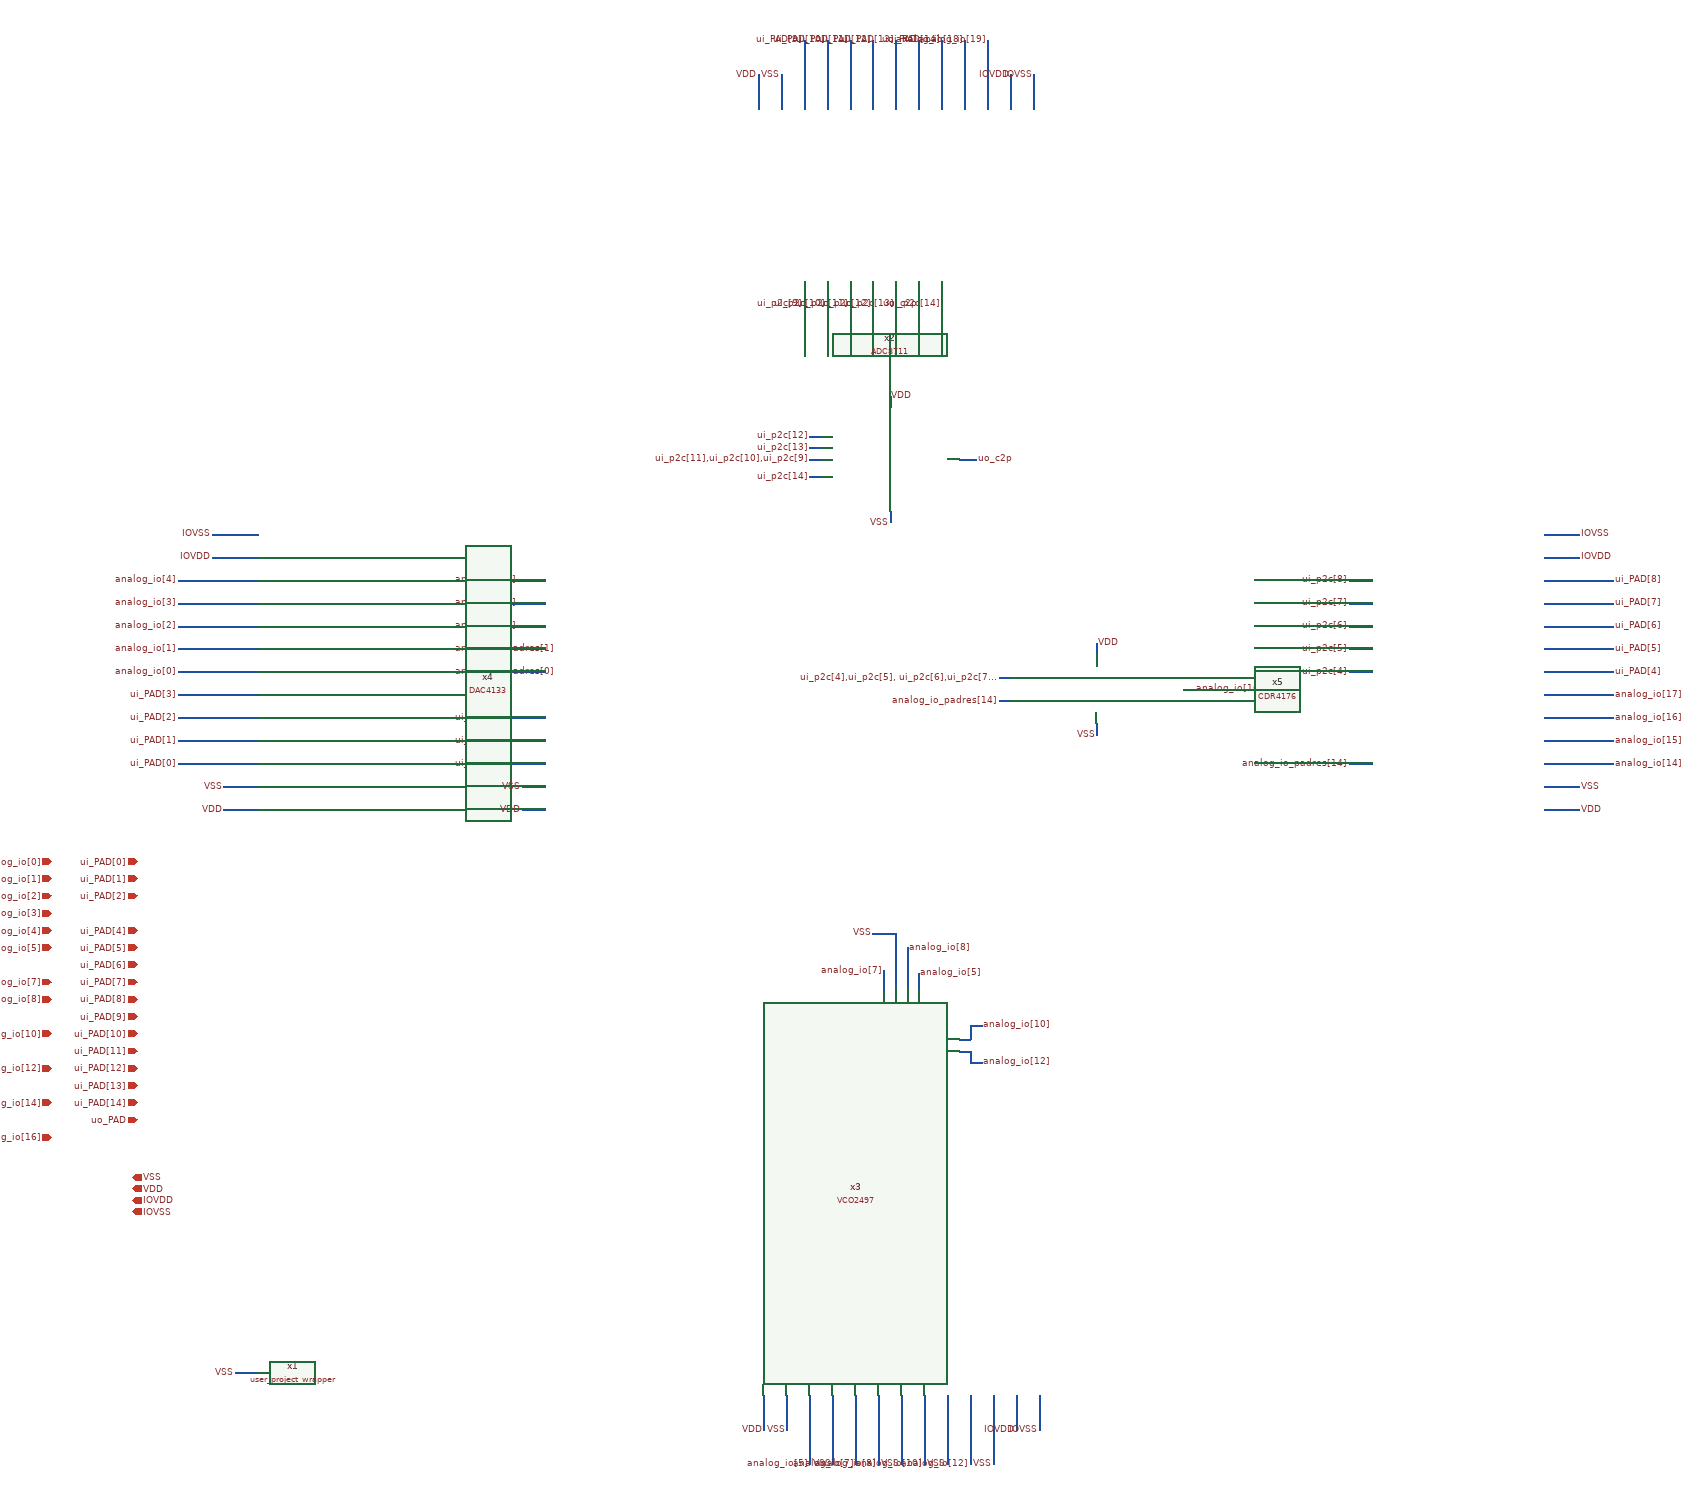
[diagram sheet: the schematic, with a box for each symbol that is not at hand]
v {xschem version=3.4.8RC file_version=1.3}
G {}
K {}
V {}
S {}
F {}
E {}
N 300 -1180 500 -1180 {lab=ui_p2c[2]}
N 2240 -1500 2300 -1500 {lab=IOVSS}
N 2240 -1460 2300 -1460 {lab=IOVDD}
N 2240 -1420 2360 -1420 {lab=ui_PAD[8]}
N 2240 -1100 2360 -1100 {lab=analog_io[14]}
N 2240 -1380 2360 -1380 {lab=ui_PAD[7]}
N 2240 -1260 2360 -1260 {lab=ui_PAD[4]}
N 2240 -1140 2360 -1140 {lab=analog_io[15]}
N 960 0 960 120 {lab=analog_io[5]}
N 1000 0 1000 120 {lab=VSS}
N 1040 0 1040 120 {lab=analog_io[7]}
N 1080 0 1080 120 {lab=analog_io[8]}
N 1120 0 1120 120 {lab=VSS}
N 1160 0 1160 120 {lab=analog_io[10]}
N 1200 0 1200 120 {lab=VSS}
N 1240 0 1240 120 {lab=analog_io[12]}
N 1280 0 1280 120 {lab=VSS}
N -40 -40 0 -40 {lab=VSS}
N 2240 -1340 2360 -1340 {lab=ui_PAD[6]}
N 2240 -1300 2360 -1300 {lab=ui_PAD[5]}
N 2240 -1180 2360 -1180 {lab=analog_io[16]}
N 2240 -1220 2360 -1220 {lab=analog_io[17]}
N 300 -1140 500 -1140 {lab=ui_p2c[1]}
N 300 -1100 500 -1100 {lab=ui_p2c[0]}
N -140 -1420 0 -1420 {lab=analog_io[4]}
N -140 -1380 0 -1380 {lab=analog_io[3]}
N -140 -1340 0 -1340 {lab=analog_io[2]}
N -140 -1300 0 -1300 {lab=analog_io[1]}
N -140 -1260 0 -1260 {lab=analog_io[0]}
N -140 -1220 0 -1220 {lab=ui_PAD[3]}
N -140 -1180 0 -1180 {lab=ui_PAD[2]}
N -140 -1140 0 -1140 {lab=ui_PAD[1]}
N -140 -1100 0 -1100 {lab=ui_PAD[0]}
N -80 -1500 -0 -1500 {lab=IOVSS}
N -80 -1460 -0 -1460 {lab=IOVDD}
N -60 -1060 -0 -1060 {lab=VSS}
N -60 -1020 -0 -1020 {lab=VDD}
N 880 0 880 60 {lab=VDD}
N 920 0 920 60 {lab=VSS}
N 1320 0 1320 60 {lab=IOVDD}
N 1360 0 1360 60 {lab=IOVSS}
N 2240 -1020 2300 -1020 {lab=VDD}
N 2240 -1060 2300 -1060 {lab=VSS}
N 1900 -1100 1940 -1100 {lab=analog_io_padres[14]}
N 1900 -1420 1940 -1420 {lab=ui_p2c[8]}
N 1900 -1380 1940 -1380 {lab=ui_p2c[7]}
N 1900 -1340 1940 -1340 {lab=ui_p2c[6]}
N 1900 -1300 1940 -1300 {lab=ui_p2c[5]}
N 1900 -1260 1940 -1260 {lab=ui_p2c[4]}
N 870 -2300 870 -2240 {lab=VDD}
N 910 -2300 910 -2240 {lab=VSS}
N 950 -2360 950 -2240 {lab=ui_PAD[9]}
N 990 -2360 990 -2240 {lab=ui_PAD[10]}
N 1030 -2360 1030 -2240 {lab=ui_PAD[11]}
N 1070 -2360 1070 -2240 {lab=ui_PAD[12]}
N 1110 -2360 1110 -2240 {lab=ui_PAD[13]}
N 1150 -2360 1150 -2240 {lab=uo_PAD}
N 1190 -2360 1190 -2240 {lab=ui_PAD[14]}
N 1230 -2360 1230 -2240 {lab=analog_io[18]}
N 1270 -2360 1270 -2240 {lab=analog_io[19]}
N 1310 -2300 1310 -2240 {lab=IOVDD}
N 1350 -2300 1350 -2240 {lab=IOVSS}
N 950 -1940 950 -1900 {lab=ui_p2c[9]}
N 990 -1940 990 -1900 {lab=ui_p2c[10]}
N 1030 -1940 1030 -1900 {lab=ui_p2c[11]}
N 1070 -1940 1070 -1900 {lab=ui_p2c[12]}
N 1110 -1940 1110 -1900 {lab=ui_p2c[13]}
N 1150 -1940 1150 -1900 {lab=uo_c2p}
N 1190 -1940 1190 -1900 {lab=ui_p2c[14]}
N 1610 -1230 1630 -1230 {lab=analog_io[16]}
N 1290 -1210 1310 -1210 {lab=analog_io_padres[14]}
N 1290 -1250 1310 -1250 {lab="ui_p2c[4],ui_p2c[5],
ui_p2c[6],ui_p2c[7],
ui_p2c[8]"}
N 1460 -1310 1460 -1290 {lab=VDD}
N 1460 -1170 1460 -1150 {lab=VSS}
N 1100 -1740 1100 -1720 {lab=VDD}
N 1100 -1540 1100 -1520 {lab=VSS}
N 960 -1600 980 -1600 {lab=ui_p2c[14]}
N 1220 -1630 1250 -1630 {lab=uo_c2p}
N 960 -1650 980 -1650 {lab=ui_p2c[13]}
N 960 -1670 980 -1670 {lab=ui_p2c[12]}
N 960 -1630 980 -1630 {lab=ui_p2c[11],ui_p2c[10],ui_p2c[9]}
N 1130 -780 1130 -710 {lab=analog_io[8]}
N 1220 -620 1240 -620 {lab=analog_io[10]}
N 1240 -645 1240 -620 {lab=analog_io[10]}
N 1240 -645 1260 -645 {lab=analog_io[10]}
N 1220 -600 1240 -600 {lab=analog_io[12]}
N 1240 -600 1240 -580 {lab=analog_io[12]}
N 1240 -580 1260 -580 {lab=analog_io[12]}
N 460 -1060 500 -1060 {lab=VSS}
N 460 -1020 500 -1020 {lab=VDD}
N 340 -1420 500 -1420 {lab=analog_io[4]}
N 340 -1380 500 -1380 {lab=analog_io[3]}
N 340 -1340 500 -1340 {lab=analog_io[2]}
N 300 -1300 500 -1300 {lab=analog_io_padres[1]}
N 300 -1260 500 -1260 {lab=analog_io_padres[0]}
N 1108.75 -805 1108.75 -710 {lab=VSS}
N 1070 -805 1108.75 -805 {lab=VSS}
N 1088.75 -740 1088.75 -703.75 {lab=analog_io[7]}
N 1088.75 -740 1090 -740 {lab=analog_io[7]}
N 1148.75 -735 1148.75 -705.9375 {lab=analog_io[5]}
N 1148.75 -735 1150 -735 {lab=analog_io[5]}
C {lab_wire.sym} 1030 -2360 3 1 {name=p12 sig_type=std_logic lab=ui_PAD[11]	}
C {lab_wire.sym} 990 -2360 3 1 {name=p13 sig_type=std_logic lab=ui_PAD[10]	}
C {lab_wire.sym} 1190 -2360 3 1 {name=p15 sig_type=std_logic lab=ui_PAD[14]	}
C {lab_wire.sym} 1070 -2360 3 1 {name=p16 sig_type=std_logic lab=ui_PAD[12]	}
C {lab_wire.sym} 950 -2360 3 1 {name=p17 sig_type=std_logic lab=ui_PAD[9]	}
C {lab_wire.sym} 1110 -2360 3 1 {name=p18 sig_type=std_logic lab=ui_PAD[13]	}
C {lab_wire.sym} 1150 -2360 3 1 {name=p19 sig_type=std_logic lab=uo_PAD	}
C {lab_wire.sym} 910 -2300 3 1 {name=p23 sig_type=std_logic lab=VSS}
C {lab_wire.sym} 870 -2300 3 1 {name=p24 sig_type=std_logic lab=VDD	}
C {lab_wire.sym} 340 -1340 0 1 {name=p45 sig_type=std_logic lab=analog_io[2]	}
C {lab_wire.sym} 340 -1300 0 1 {name=p46 sig_type=std_logic lab=analog_io_padres[1]	}
C {lab_wire.sym} -140 -1420 0 0 {name=p59 sig_type=std_logic lab=analog_io[4]	}
C {lab_wire.sym} 2300 -1060 0 1 {name=p63 sig_type=std_logic lab=VSS}
C {lab_wire.sym} 2300 -1020 0 1 {name=p64 sig_type=std_logic lab=VDD}
C {lab_wire.sym} 2360 -1180 0 1 {name=p67 sig_type=std_logic lab=analog_io[16]}
C {lab_wire.sym} 2360 -1340 0 1 {name=p68 sig_type=std_logic lab=ui_PAD[6]}
C {lab_wire.sym} 1900 -1100 0 0 {name=p72 sig_type=std_logic lab=analog_io_padres[14]}
C {lab_wire.sym} 2360 -1380 0 1 {name=p77 sig_type=std_logic lab=ui_PAD[7]	}
C {lab_wire.sym} 2360 -1260 0 1 {name=p78 sig_type=std_logic lab=ui_PAD[4]	}
C {lab_wire.sym} 2360 -1100 0 1 {name=p79 sig_type=std_logic lab=analog_io[14]	}
C {lab_wire.sym} 920 60 3 0 {name=p82 sig_type=std_logic lab=VSS}
C {lab_wire.sym} 1000 120 3 0 {name=p84 sig_type=std_logic lab=VSS	}
C {lab_wire.sym} 1040 120 3 0 {name=p85 sig_type=std_logic lab=analog_io[7]	}
C {lab_wire.sym} 1080 120 3 0 {name=p86 sig_type=std_logic lab=analog_io[8]	}
C {lab_wire.sym} 1120 120 3 0 {name=p87 sig_type=std_logic lab=VSS	}
C {lab_wire.sym} 1160 120 3 0 {name=p88 sig_type=std_logic lab=analog_io[10]	}
C {lab_wire.sym} 1200 120 3 0 {name=p89 sig_type=std_logic lab=VSS	}
C {lab_wire.sym} 1240 120 3 0 {name=p90 sig_type=std_logic lab=analog_io[12]	}
C {lab_wire.sym} 1280 120 3 0 {name=p91 sig_type=std_logic lab=VSS	}
C {lab_wire.sym} 960 120 3 0 {name=p102 sig_type=std_logic lab=analog_io[5]	}
C {iopin.sym} -360 -630 2 0 {name=p103 lab=analog_io[10]}
C {iopin.sym} -360 -810 2 0 {name=p104 lab=analog_io[4]}
C {iopin.sym} -360 -930 2 0 {name=p105 lab=analog_io[0]}
C {iopin.sym} -360 -900 2 0 {name=p106 lab=analog_io[1]}
C {iopin.sym} -360 -780 2 0 {name=p116 lab=analog_io[5]}
C {iopin.sym} -360 -720 2 0 {name=p118 lab=analog_io[7]}
C {iopin.sym} -360 -570 2 0 {name=p120 lab=analog_io[12]}
C {iopin.sym} -360 -510 2 0 {name=p122 lab=analog_io[14]}
C {iopin.sym} -360 -450 2 0 {name=p124 lab=analog_io[16]}
C {iopin.sym} -360 -690 2 0 {name=p128 lab=analog_io[8]}
C {iopin.sym} -210 -930 2 0 {name=p129 lab=ui_PAD[0]}
C {iopin.sym} -210 -900 2 0 {name=p131 lab=ui_PAD[1]}
C {iopin.sym} -210 -810 2 0 {name=p134 lab=ui_PAD[4]}
C {iopin.sym} -210 -780 2 0 {name=p137 lab=ui_PAD[5]}
C {iopin.sym} -210 -720 2 0 {name=p138 lab=ui_PAD[7]}
C {iopin.sym} -360 -870 2 0 {name=p139 lab=analog_io[2]}
C {iopin.sym} -360 -840 2 0 {name=p140 lab=analog_io[3]}
C {iopin.sym} -210 -690 2 0 {name=p141 lab=ui_PAD[8]}
C {iopin.sym} -210 -750 2 0 {name=p108 lab=ui_PAD[6]}
C {iopin.sym} -210 -480 2 0 {name=p114 lab=uo_PAD}
C {iopin.sym} -210 -870 2 0 {name=p142 lab=ui_PAD[2]}
C {iopin.sym} -220 -380 0 1 {name=p130 lab=VSS}
C {iopin.sym} -220 -360 0 1 {name=p133 lab=VDD}
C {iopin.sym} -220 -340 0 1 {name=p135 lab=IOVDD}
C {iopin.sym} -220 -320 0 1 {name=p143 lab=IOVSS}
C {lab_wire.sym} -40 -40 0 0 {name=p156 sig_type=std_logic lab=VSS}
C {lab_wire.sym} -140 -1380 0 0 {name=p159 sig_type=std_logic lab=analog_io[3]	}
C {lab_wire.sym} -140 -1260 0 0 {name=p160 sig_type=std_logic lab=analog_io[0]	}
C {lab_wire.sym} -60 -1020 0 0 {name=p161 sig_type=std_logic lab=VDD}
C {lab_wire.sym} -60 -1060 0 0 {name=p162 sig_type=std_logic lab=VSS}
C {lab_wire.sym} -140 -1100 0 0 {name=p163 sig_type=std_logic lab=ui_PAD[0]	}
C {lab_wire.sym} -140 -1140 0 0 {name=p164 sig_type=std_logic lab=ui_PAD[1]	}
C {lab_wire.sym} -140 -1180 0 0 {name=p165 sig_type=std_logic lab=ui_PAD[2]	}
C {lab_wire.sym} -140 -1220 0 0 {name=p166 sig_type=std_logic lab=ui_PAD[3]	}
C {lab_wire.sym} -140 -1300 0 0 {name=p167 sig_type=std_logic lab=analog_io[1]	}
C {lab_wire.sym} -140 -1340 0 0 {name=p168 sig_type=std_logic lab=analog_io[2]	}
C {lab_wire.sym} -80 -1500 0 0 {name=p170 sig_type=std_logic lab=IOVSS}
C {lab_wire.sym} -80 -1460 0 0 {name=p171 sig_type=std_logic lab=IOVDD}
C {user_project_wrapper.sym} 0 0 0 0 {name=x1
lock=true

}
C {iopin.sym} -210 -660 2 0 {name=p172 lab=ui_PAD[9]}
C {iopin.sym} -210 -630 2 0 {name=p173 lab=ui_PAD[10]}
C {iopin.sym} -210 -600 2 0 {name=p174 lab=ui_PAD[11]}
C {iopin.sym} -210 -570 2 0 {name=p175 lab=ui_PAD[12]}
C {iopin.sym} -210 -540 2 0 {name=p176 lab=ui_PAD[13]}
C {iopin.sym} -210 -510 2 0 {name=p177 lab=ui_PAD[14]}
C {lab_wire.sym} 2360 -1300 0 1 {name=p9 sig_type=std_logic lab=ui_PAD[5]}
C {lab_wire.sym} 2360 -1420 0 1 {name=p25 sig_type=std_logic lab=ui_PAD[8]	}
C {lab_wire.sym} 340 -1420 0 1 {name=p30 sig_type=std_logic lab=analog_io[4]	}
C {lab_wire.sym} 340 -1380 0 1 {name=p31 sig_type=std_logic lab=analog_io[3]	}
C {lab_wire.sym} 340 -1260 0 1 {name=p53 sig_type=std_logic lab=analog_io_padres[0]	}
C {lab_wire.sym} 340 -1180 0 1 {name=p54 sig_type=std_logic lab=ui_p2c[2]	}
C {lab_wire.sym} 340 -1140 0 1 {name=p36 sig_type=std_logic lab=ui_p2c[1]	}
C {lab_wire.sym} 340 -1100 0 1 {name=p37 sig_type=std_logic lab=ui_p2c[0]	}
C {lab_wire.sym} 1900 -1260 0 0 {name=p39 sig_type=std_logic lab=ui_p2c[4]	}
C {lab_wire.sym} 1900 -1300 0 0 {name=p40 sig_type=std_logic lab=ui_p2c[5]	}
C {lab_wire.sym} 1900 -1340 0 0 {name=p43 sig_type=std_logic lab=ui_p2c[6]	}
C {lab_wire.sym} 1900 -1380 0 0 {name=p44 sig_type=std_logic lab=ui_p2c[7]	}
C {lab_wire.sym} 1900 -1420 0 0 {name=p47 sig_type=std_logic lab=ui_p2c[8]	}
C {lab_wire.sym} 950 -1900 3 0 {name=p10 sig_type=std_logic lab=ui_p2c[9]	}
C {lab_wire.sym} 1150 -1900 3 0 {name=p48 sig_type=std_logic lab=uo_c2p	}
C {lab_wire.sym} 990 -1900 3 0 {name=p49 sig_type=std_logic lab=ui_p2c[10]	}
C {lab_wire.sym} 1030 -1900 3 0 {name=p51 sig_type=std_logic lab=ui_p2c[11]	}
C {lab_wire.sym} 1070 -1900 3 0 {name=p52 sig_type=std_logic lab=ui_p2c[12]	}
C {lab_wire.sym} 1110 -1900 3 0 {name=p2 sig_type=std_logic lab=ui_p2c[13]	}
C {lab_wire.sym} 1190 -1900 3 0 {name=p27 sig_type=std_logic lab=ui_p2c[14]	}
C {lab_wire.sym} 1630 -1230 0 1 {name=p1 sig_type=std_logic lab=analog_io[16]}
C {lab_wire.sym} 1290 -1210 0 0 {name=p4 sig_type=std_logic lab=analog_io_padres[14]}
C {lab_wire.sym} 1290 -1250 0 0 {name=p5 sig_type=std_logic lab="ui_p2c[4],ui_p2c[5],
ui_p2c[6],ui_p2c[7],
ui_p2c[8]"	}
C {lab_wire.sym} 1460 -1310 0 1 {name=p6 sig_type=std_logic lab=VDD}
C {lab_wire.sym} 1460 -1150 2 1 {name=p7 sig_type=std_logic lab=VSS}
C {lab_wire.sym} 1100 -1740 0 1 {name=p8 sig_type=std_logic lab=VDD	}
C {lab_wire.sym} 1100 -1520 2 1 {name=p11 sig_type=std_logic lab=VSS}
C {lab_wire.sym} 960 -1600 2 1 {name=p26 sig_type=std_logic lab=ui_p2c[14]	}
C {lab_wire.sym} 1250 -1630 2 0 {name=p41 sig_type=std_logic lab=uo_c2p	}
C {lab_wire.sym} 960 -1650 0 0 {name=p50 sig_type=std_logic lab=ui_p2c[13]	}
C {lab_wire.sym} 960 -1670 0 0 {name=p56 sig_type=std_logic lab=ui_p2c[12]	}
C {lab_wire.sym} 960 -1630 2 1 {name=p57 sig_type=std_logic lab="ui_p2c[11],ui_p2c[10],ui_p2c[9]"	}
C {lab_wire.sym} 1070 -805 0 0 {name=p58 sig_type=std_logic lab=VSS}
C {lab_pin.sym} 1090 -740 0 0 {name=p65 sig_type=std_logic lab=analog_io[7]}
C {lab_pin.sym} 1130 -780 2 0 {name=p66 sig_type=std_logic lab=analog_io[8]}
C {lab_pin.sym} 1150 -735 2 0 {name=p69 sig_type=std_logic lab=analog_io[5]}
C {lab_pin.sym} 1260 -645 2 0 {name=p70 sig_type=std_logic lab=analog_io[10]}
C {lab_pin.sym} 1260 -580 2 0 {name=p71 sig_type=std_logic lab=analog_io[12]}
C {VCO2497.sym} 860 -620 0 0 {name=x3}
C {lab_wire.sym} 2300 -1500 0 1 {name=p14 sig_type=std_logic lab=IOVSS}
C {lab_wire.sym} 2300 -1460 0 1 {name=p20 sig_type=std_logic lab=IOVDD	}
C {DAC4133.sym} 650 -1220 0 0 {name=x4}
C {lab_wire.sym} 880 60 3 0 {name=p21 sig_type=std_logic lab=VDD}
C {lab_wire.sym} 1360 60 3 0 {name=p22 sig_type=std_logic lab=IOVSS}
C {lab_wire.sym} 1320 60 3 0 {name=p29 sig_type=std_logic lab=IOVDD}
C {lab_wire.sym} 2360 -1140 0 1 {name=p42 sig_type=std_logic lab=analog_io[15]}
C {lab_wire.sym} 2360 -1220 0 1 {name=p55 sig_type=std_logic lab=analog_io[17]}
C {lab_wire.sym} 1230 -2360 3 1 {name=p74 sig_type=std_logic lab=analog_io[18]}
C {lab_wire.sym} 1270 -2360 3 1 {name=p75 sig_type=std_logic lab=analog_io[19]}
C {lab_wire.sym} 1310 -2300 3 1 {name=p76 sig_type=std_logic lab=IOVDD}
C {lab_wire.sym} 1350 -2300 3 1 {name=p80 sig_type=std_logic lab=IOVSS}
C {lab_wire.sym} 460 -1060 0 0 {name=p38 sig_type=std_logic lab=VSS}
C {lab_wire.sym} 460 -1020 0 0 {name=p81 sig_type=std_logic lab=VDD}
C {CDR4176/CDR4176.sym} 1460 -1230 0 0 {name=x5}
C {IHP__MPC2585/dependencies/IHP__ADC8711/ADC8711-main/schematic/xschem/ADC8711.sym} 960 -1520 0 0 {name=x2}
